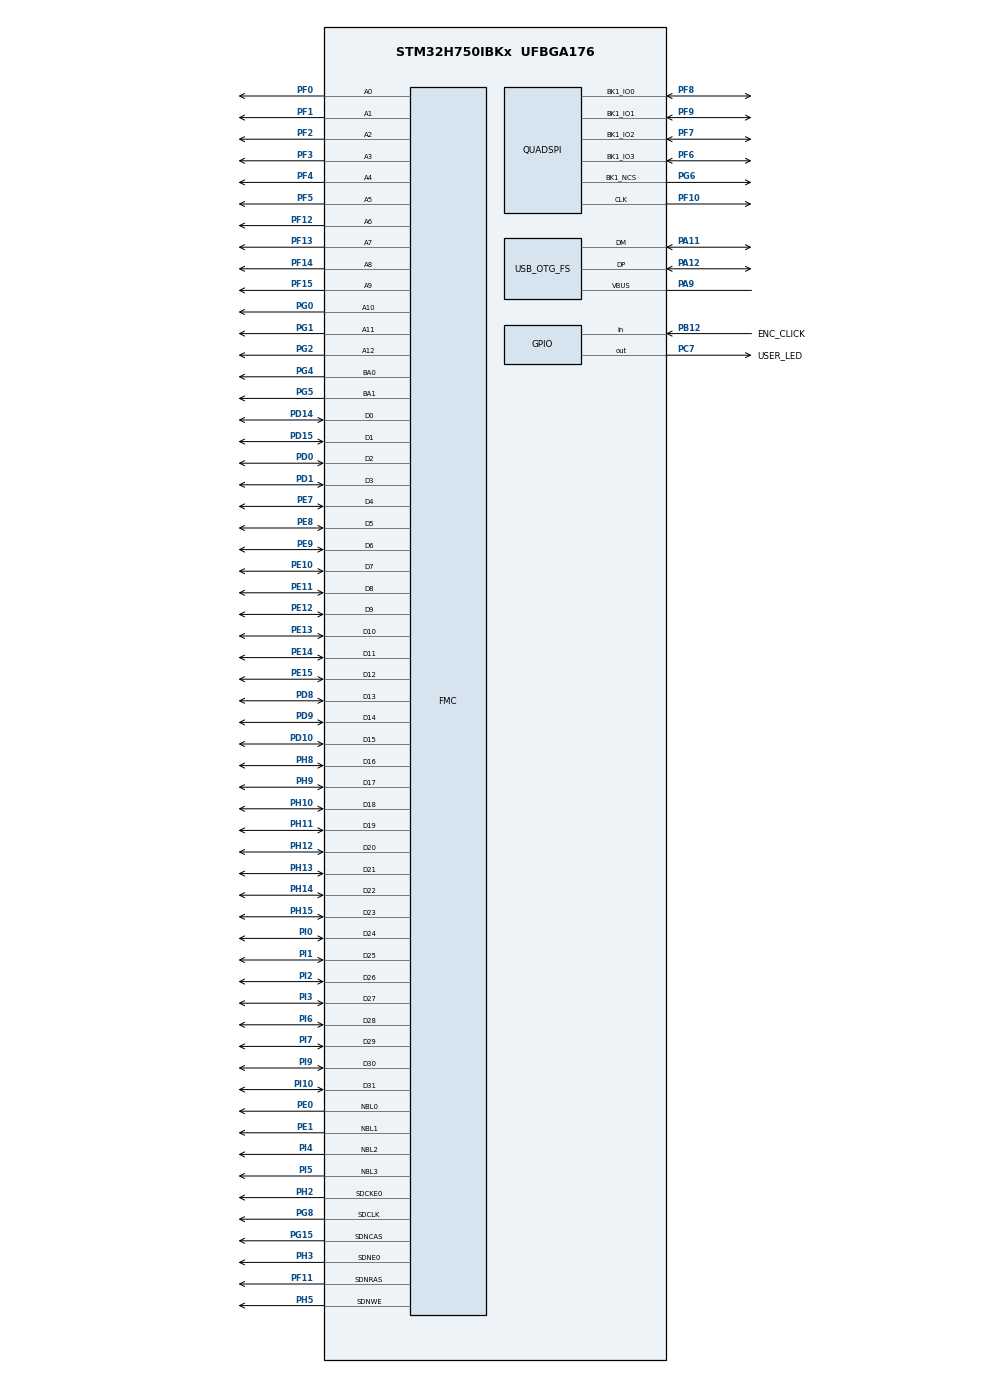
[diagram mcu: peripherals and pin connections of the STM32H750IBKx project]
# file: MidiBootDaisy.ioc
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CORTEX_M7.MPU_Control=__NULL
IWDG1.Prescaler=IWDG_PRESCALER_128
IWDG1.Reload=8*32000/128
IWDG1.Window=8*32000/128
Mcu.Family=STM32H7
Mcu.Name=STM32H750IBKx
Mcu.Package=UFBGA176
NVIC.OTG_FS_IRQn=true\:0\:0\:false\:false\:true\:false\:true
NVIC.PriorityGroup=NVIC_PRIORITYGROUP_4
NVIC.QUADSPI_IRQn=true\:0\:0\:false\:false\:true\:true\:true
PA11.GPIO_Speed=GPIO_SPEED_FREQ_VERY_HIGH
PA11.Mode=Device_Only
PA11.Signal=USB_OTG_FS_DM
PA12.GPIO_Speed=GPIO_SPEED_FREQ_VERY_HIGH
PA12.Mode=Device_Only
PA12.Signal=USB_OTG_FS_DP
PA13\ (JTMS/SWDIO).Mode=JTAG_4_pins
PA13\ (JTMS/SWDIO).Signal=DEBUG_JTMS-SWDIO
PA14\ (JTCK/SWCLK).Mode=JTAG_4_pins
PA14\ (JTCK/SWCLK).Signal=DEBUG_JTCK-SWCLK
PA15\ (JTDI).Mode=JTAG_4_pins
PA15\ (JTDI).Signal=DEBUG_JTDI
PA9.Mode=Activate_VBUS
PA9.Signal=USB_OTG_FS_VBUS
PB12.GPIO_Label=ENC_CLICK
PB12.GPIO_PuPd=GPIO_PULLUP
PB12.Signal=GPIO_Input
PB14.Signal=USB_OTG_HS_DM
PB15.Signal=USB_OTG_HS_DP
PB3\ (JTDO/TRACESWO).Mode=JTAG_4_pins
PB3\ (JTDO/TRACESWO).Signal=DEBUG_JTDO-SWO
PC7.GPIO_Label=USER_LED
PC7.Signal=GPIO_Output
PD0.Signal=FMC_D2_DA2
PD1.Signal=FMC_D3_DA3
PD10.Signal=FMC_D15_DA15
PD14.Signal=FMC_D0_DA0
PD15.Signal=FMC_D1_DA1
PD8.Signal=FMC_D13_DA13
PD9.Signal=FMC_D14_DA14
PE0.Signal=FMC_NBL0
PE1.Signal=FMC_NBL1
PE10.Signal=FMC_D7_DA7
PE11.Signal=FMC_D8_DA8
PE12.Signal=FMC_D9_DA9
PE13.Signal=FMC_D10_DA10
PE14.Signal=FMC_D11_DA11
PE15.Signal=FMC_D12_DA12
PE7.Signal=FMC_D4_DA4
PE8.Signal=FMC_D5_DA5
PE9.Signal=FMC_D6_DA6
PF0.Signal=FMC_A0
PF1.Signal=FMC_A1
PF10.GPIO_Speed=GPIO_SPEED_FREQ_VERY_HIGH
PF10.Mode=Single Bank 1
PF10.Signal=QUADSPI_CLK
PF11.Signal=FMC_SDNRAS
PF12.Signal=FMC_A6
PF13.Signal=FMC_A7
PF14.Signal=FMC_A8
PF15.Signal=FMC_A9
PF2.Signal=FMC_A2
PF3.Signal=FMC_A3
PF4.Signal=FMC_A4
PF5.Signal=FMC_A5
PF6.GPIO_Speed=GPIO_SPEED_FREQ_VERY_HIGH
PF6.Mode=Single Bank 1
PF6.Signal=QUADSPI_BK1_IO3
PF7.GPIO_Speed=GPIO_SPEED_FREQ_VERY_HIGH
PF7.Mode=Single Bank 1
PF7.Signal=QUADSPI_BK1_IO2
PF8.GPIO_Speed=GPIO_SPEED_FREQ_VERY_HIGH
PF8.Mode=Single Bank 1
PF8.Signal=QUADSPI_BK1_IO0
PF9.GPIO_Speed=GPIO_SPEED_FREQ_VERY_HIGH
PF9.Mode=Single Bank 1
PF9.Signal=QUADSPI_BK1_IO1
PG0.Signal=FMC_A10
PG1.Signal=FMC_A11
PG15.Signal=FMC_SDNCAS
PG2.Signal=FMC_A12
PG4.Signal=FMC_A14_BA0
PG5.Signal=FMC_A15_BA1
PG6.GPIO_Speed=GPIO_SPEED_FREQ_VERY_HIGH
PG6.Mode=Single Bank 1
PG6.Signal=QUADSPI_BK1_NCS
PG8.Signal=FMC_SDCLK
PH0-OSC_IN\ (PH0).Mode=HSE-External-Oscillator
PH0-OSC_IN\ (PH0).Signal=RCC_OSC_IN
PH1-OSC_OUT\ (PH1).Mode=HSE-External-Oscillator
PH1-OSC_OUT\ (PH1).Signal=RCC_OSC_OUT
PH10.Signal=FMC_D18
PH11.Signal=FMC_D19
PH12.Signal=FMC_D20
PH13.Signal=FMC_D21
PH14.Signal=FMC_D22
PH15.Signal=FMC_D23
PH2.Mode=SdramChipSelect1_1
PH2.Signal=FMC_SDCKE0
PH3.Mode=SdramChipSelect1_1
PH3.Signal=FMC_SDNE0
PH5.Signal=FMC_SDNWE
PH8.Signal=FMC_D16
PH9.Signal=FMC_D17
PI0.Signal=FMC_D24
PI1.Signal=FMC_D25
PI10.Signal=FMC_D31
PI2.Signal=FMC_D26
PI3.Signal=FMC_D27
PI4.Signal=FMC_NBL2
PI5.Signal=FMC_NBL3
PI6.Signal=FMC_D28
PI7.Signal=FMC_D29
PI9.Signal=FMC_D30
ProjectManager.HeapSize=0x2000
ProjectManager.StackSize=0x4000
ProjectManager.TargetToolchain=Makefile
QUADSPI.ChipSelectHighTime=QSPI_CS_HIGH_TIME_2_CYCLE
QUADSPI.ClockPrescaler=1
RCC.ADCCLockSelection=RCC_ADCCLKSOURCE_PLL3
RCC.ADCFreq_Value=49166666.666666664
RCC.APB1Freq_Value=100000000
RCC.APB2Freq_Value=100000000
RCC.APB3Freq_Value=100000000
RCC.APB4Freq_Value=100000000
RCC.CKPERSourceSelection=RCC_CLKPSOURCE_HSE
RCC.CortexFreq_Value=400000000
RCC.D1PPRE=RCC_APB3_DIV2
RCC.D2PPRE1=RCC_APB1_DIV2
RCC.D2PPRE2=RCC_APB2_DIV2
RCC.D3PPRE=RCC_APB4_DIV2
RCC.DIVM1=4
RCC.DIVM2=4
RCC.DIVM3=6
RCC.DIVN1=200
RCC.DIVN2=84
RCC.DIVN3=295
RCC.DIVP2=8
RCC.DIVP3=4
RCC.DIVQ1=5
RCC.DIVQ3=4
RCC.DIVR3=16
RCC.FMCCLockSelection=RCC_FMCCLKSOURCE_PLL2
RCC.HCLKFreq_Value=200000000
RCC.HPRE=RCC_HCLK_DIV2
RCC.HSE_VALUE=16000000
RCC.PLL2FRACN=0
RCC.PLL3FRACN=0
RCC.PLLFRACN=0
RCC.PLLSourceVirtual=RCC_PLLSOURCE_HSE
RCC.SAI1CLockSelection=RCC_SAI1CLKSOURCE_PLL3
RCC.SAI23CLockSelection=RCC_SAI23CLKSOURCE_PLL3
RCC.SDMMC1CLockSelection=RCC_SDMMCCLKSOURCE_PLL2
RCC.SYSCLKFreq_VALUE=400000000
RCC.SYSCLKSource=RCC_SYSCLKSOURCE_PLLCLK
RCC.USBCLockSelection=RCC_USBCLKSOURCE_HSI48
RCC.USBFreq_Value=48000000
SH.FMC_A0.0=FMC_A0,13b-sda1
SH.FMC_A1.0=FMC_A1,13b-sda1
SH.FMC_A10.0=FMC_A10,13b-sda1
SH.FMC_A11.0=FMC_A11,13b-sda1
SH.FMC_A12.0=FMC_A12,13b-sda1
SH.FMC_A14_BA0.0=FMC_BA0,FourSdramBanks1
SH.FMC_A15_BA1.0=FMC_BA1,FourSdramBanks1
SH.FMC_A2.0=FMC_A2,13b-sda1
SH.FMC_A3.0=FMC_A3,13b-sda1
SH.FMC_A4.0=FMC_A4,13b-sda1
SH.FMC_A5.0=FMC_A5,13b-sda1
SH.FMC_A6.0=FMC_A6,13b-sda1
SH.FMC_A7.0=FMC_A7,13b-sda1
SH.FMC_A8.0=FMC_A8,13b-sda1
SH.FMC_A9.0=FMC_A9,13b-sda1
SH.FMC_D0_DA0.0=FMC_D0,sd-32b-d1
SH.FMC_D10_DA10.0=FMC_D10,sd-32b-d1
SH.FMC_D11_DA11.0=FMC_D11,sd-32b-d1
SH.FMC_D12_DA12.0=FMC_D12,sd-32b-d1
SH.FMC_D13_DA13.0=FMC_D13,sd-32b-d1
SH.FMC_D14_DA14.0=FMC_D14,sd-32b-d1
SH.FMC_D15_DA15.0=FMC_D15,sd-32b-d1
SH.FMC_D16.0=FMC_D16,sd-32b-d1
SH.FMC_D17.0=FMC_D17,sd-32b-d1
SH.FMC_D18.0=FMC_D18,sd-32b-d1
SH.FMC_D19.0=FMC_D19,sd-32b-d1
SH.FMC_D1_DA1.0=FMC_D1,sd-32b-d1
SH.FMC_D20.0=FMC_D20,sd-32b-d1
SH.FMC_D21.0=FMC_D21,sd-32b-d1
SH.FMC_D22.0=FMC_D22,sd-32b-d1
SH.FMC_D23.0=FMC_D23,sd-32b-d1
SH.FMC_D24.0=FMC_D24,sd-32b-d1
SH.FMC_D25.0=FMC_D25,sd-32b-d1
SH.FMC_D26.0=FMC_D26,sd-32b-d1
SH.FMC_D27.0=FMC_D27,sd-32b-d1
SH.FMC_D28.0=FMC_D28,sd-32b-d1
SH.FMC_D29.0=FMC_D29,sd-32b-d1
SH.FMC_D2_DA2.0=FMC_D2,sd-32b-d1
SH.FMC_D30.0=FMC_D30,sd-32b-d1
SH.FMC_D31.0=FMC_D31,sd-32b-d1
SH.FMC_D3_DA3.0=FMC_D3,sd-32b-d1
SH.FMC_D4_DA4.0=FMC_D4,sd-32b-d1
SH.FMC_D5_DA5.0=FMC_D5,sd-32b-d1
SH.FMC_D6_DA6.0=FMC_D6,sd-32b-d1
SH.FMC_D7_DA7.0=FMC_D7,sd-32b-d1
SH.FMC_D8_DA8.0=FMC_D8,sd-32b-d1
SH.FMC_D9_DA9.0=FMC_D9,sd-32b-d1
SH.FMC_NBL0.0=FMC_NBL0,Sd4ByteEnable1
SH.FMC_NBL1.0=FMC_NBL1,Sd4ByteEnable1
SH.FMC_NBL2.0=FMC_NBL2,Sd4ByteEnable1
SH.FMC_NBL3.0=FMC_NBL3,Sd4ByteEnable1
SH.FMC_SDCLK.0=FMC_SDCLK,13b-sda1
SH.FMC_SDNCAS.0=FMC_SDNCAS,13b-sda1
SH.FMC_SDNRAS.0=FMC_SDNRAS,13b-sda1
SH.FMC_SDNWE.0=FMC_SDNWE,13b-sda1
USB_DEVICE.CLASS_NAME_FS=AUDIO
USB_DEVICE.MANUFACTURER_STRING-AUDIO_FS=Electrosmith
USB_DEVICE.PID_AUDIO_FS=0xDADA
USB_DEVICE.PRODUCT_STRING_AUDIO_FS=OWL-BOOT
USB_DEVICE.USBD_AUDIO_FREQ-AUDIO_FS=48000
USB_DEVICE.USBD_MAX_NUM_CONFIGURATION-AUDIO_FS=5
USB_DEVICE.USBD_MAX_NUM_INTERFACES-AUDIO_FS=5
USB_DEVICE.VID-AUDIO_FS=0x0155
USB_DEVICE.VirtualMode-AUDIO_FS=Audio
USB_DEVICE.VirtualModeFS=Audio_FS
USB_OTG_FS.VirtualMode=Device_Only
VP_IWDG1_VS_IWDG.Mode=IWDG_Activate
VP_USB_DEVICE_VS_USB_DEVICE_AUDIO_FS.Mode=AUDIO_FS
board=custom

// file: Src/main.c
/* USER CODE BEGIN Header */
/**
  ******************************************************************************
  * @file           : main.c
  * @brief          : Main program body
  ******************************************************************************
  * @attention
  *
  * <h2><center>&copy; Copyright (c) 2020 STMicroelectronics.
  * All rights reserved.</center></h2>
  *
  * This software component is licensed by ST under Ultimate Liberty license
  * SLA0044, the "License"; You may not use this file except in compliance with
  * the License. You may obtain a copy of the License at:
  *                             www.st.com/SLA0044
  *
  ******************************************************************************
  */
/* USER CODE END Header */
#include "main.h"
#include "usb_device.h"

/* USER CODE BEGIN Includes */
#include "device.h"
#include "errorhandlers.h"
#include "qspicontrol.h"
#include "FirmwareHeader.h"
#include "sdram.h"
#include "crc32.h"
/* USER CODE END Includes */

IWDG_HandleTypeDef hiwdg1;

QSPI_HandleTypeDef hqspi;

SDRAM_HandleTypeDef hsdram1;

/* USER CODE BEGIN PV */
/* Private variables ---------------------------------------------------------*/
/* USER CODE END PV */

void SystemClock_Config(void);
static void MX_GPIO_Init(void);
static void MX_FMC_Init(void);
static void MX_QUADSPI_Init(void);
static void MX_IWDG1_Init(void);
/* USER CODE BEGIN PFP */
/* Private function prototypes -----------------------------------------------*/

void setup(void);
void SDRAM_Initialization_Sequence(SDRAM_HandleTypeDef *hsdram);
void loop(void);
void setMessage(const char* msg);
struct FirmwareHeader* getFirmwareHeader(void);
int loadFirmware(void);

typedef  void (*pFunction)(void);

static int testMagic(){
  return *OWLBOOT_MAGIC_ADDRESS == OWLBOOT_MAGIC_NUMBER;
}

static int testLoop(){
  // Prevent reset cycles.
  // Check if we've been reset without zeroing the magic address,
  // which might indicate a corrupt firmware.
  return *OWLBOOT_MAGIC_ADDRESS == OWLBOOT_LOOP_NUMBER;
}

static int testButton(){
#ifdef USE_BOOT1_PIN
  return !(BOOT1_GPIO_Port->IDR & BOOT1_Pin);
#else
  return 0;
#endif
}

static int testNoProgram(){
  // NOTE: this must run only if QSPI flash is:
  // a. initialized successfully
  // b. is in memory-mapped mode
  return (*(__IO uint32_t*)APPLICATION_ADDRESS) != HEADER_MAGIC;
}

static int testWatchdogReset(){
  return __HAL_RCC_GET_FLAG(RCC_FLAG_IWDG1RST) != RESET;
}

static int testFirmwareHeader(){
  struct FirmwareHeader* header = getFirmwareHeader();
  uint32_t header_crc = crc32((void*)header, header->header_size - 4, 0);
  return header->checksum != header_crc;
}

/* USER CODE END PFP */

int main(void)
{

  /* MCU Configuration--------------------------------------------------------*/

  /* Reset of all peripherals, Initializes the Flash interface and the Systick. */
  HAL_Init();

  /* Configure the system clock */
  SystemClock_Config();

  /* Initialize all configured peripherals */
  MX_GPIO_Init();
  MX_FMC_Init();
  MX_QUADSPI_Init();
  MX_IWDG1_Init();
  MX_USB_DEVICE_Init();
  /* USER CODE BEGIN 2 */

  SDRAM_Initialization_Sequence(&hsdram1);
  MPU_Config();
  if (qspi_init(QSPI_MODE_MEMORY_MAPPED) != MEMORY_OK){
    // We can end here only if QSPI settings are misconfigured
    error(RUNTIME_ERROR, "Flash init error");
  }
  else {
    if(testMagic()){
      setMessage("Bootloader starting");
    }
    else if(testButton()){
      setMessage("Bootloader requested");
      }
    else if(testLoop()){
      error(RUNTIME_ERROR, "Unexpected firmware reset");
    }
    else if(testWatchdogReset()){
      error(RUNTIME_ERROR, "Watchdog reset");
    }
    else if(testNoProgram()){
      error(RUNTIME_ERROR, "No valid firmware");
    }
    else if(testFirmwareHeader()){
      error(RUNTIME_ERROR, "Invalid firmware header");
    }
    else if (loadFirmware()){
      // jump to application code

      /* Disable all interrupts */
      __disable_irq();

      RCC->CIER = 0x00000000;

      /* Disable and reset SysTick */
      SysTick->CTRL = 0;
      SysTick->LOAD = 0;
      SysTick->VAL = 0;

      /* Clear Interrupt Enable Register & Interrupt Pending Register */
      for (int i = 0;i < 8; i++) {
    	  NVIC->ICER[i]=0xFFFFFFFF;
	      NVIC->ICPR[i]=0xFFFFFFFF;
      }

      /* put marker in to prevent reset cycles */
      *OWLBOOT_MAGIC_ADDRESS = OWLBOOT_LOOP_NUMBER;

      /* Jump to user application */
      struct FirmwareHeader* header = getFirmwareHeader();

      // Enable IWDG if firmware has option bit set
      //if ((header->options >> OPT_IWDG_OFFSET) & OPT_IWDG_MASK)
        MX_IWDG1_Init();

      uint32_t JumpAddress = *(__IO uint32_t*) (header->isr_vector_address + 4);
      pFunction jumpToApplication = (pFunction) JumpAddress;
      /* Initialize user application's Stack Pointer */
      __set_MSP(*(__IO uint32_t*) header->isr_vector_address);

      jumpToApplication();
      for(;;);
    }
  }
  MX_IWDG1_Init();

  /* Clear reset flags */
  __HAL_RCC_CLEAR_RESET_FLAGS();

  /* Clear magic */
  *OWLBOOT_MAGIC_ADDRESS = 0;

  // Initialise
  setup();

  /* USER CODE END 2 */

  /* Infinite loop */
  /* USER CODE BEGIN WHILE */
  while (1)
  {
    loop();
#ifdef USE_IWDG
    IWDG1->KR = 0xaaaa; // reset the watchdog timer
#endif
    /* USER CODE END WHILE */

  }
}

void SystemClock_Config(void)
{
  RCC_OscInitTypeDef RCC_OscInitStruct = {0};
  RCC_ClkInitTypeDef RCC_ClkInitStruct = {0};
  RCC_PeriphCLKInitTypeDef PeriphClkInitStruct = {0};

  /** Supply configuration update enable
  */
  HAL_PWREx_ConfigSupply(PWR_LDO_SUPPLY);
  /** Configure the main internal regulator output voltage
  */
  __HAL_PWR_VOLTAGESCALING_CONFIG(PWR_REGULATOR_VOLTAGE_SCALE1);

  while(!__HAL_PWR_GET_FLAG(PWR_FLAG_VOSRDY)) {}
  /** Macro to configure the PLL clock source
  */
  __HAL_RCC_PLL_PLLSOURCE_CONFIG(RCC_PLLSOURCE_HSE);
  /** Initializes the RCC Oscillators according to the specified parameters
  * in the RCC_OscInitTypeDef structure.
  */
  RCC_OscInitStruct.OscillatorType = RCC_OSCILLATORTYPE_HSI48|RCC_OSCILLATORTYPE_LSI
                              |RCC_OSCILLATORTYPE_HSE;
  RCC_OscInitStruct.HSEState = RCC_HSE_ON;
  RCC_OscInitStruct.LSIState = RCC_LSI_ON;
  RCC_OscInitStruct.HSI48State = RCC_HSI48_ON;
  RCC_OscInitStruct.PLL.PLLState = RCC_PLL_ON;
  RCC_OscInitStruct.PLL.PLLSource = RCC_PLLSOURCE_HSE;
  RCC_OscInitStruct.PLL.PLLM = 4;
  RCC_OscInitStruct.PLL.PLLN = 200;
  RCC_OscInitStruct.PLL.PLLP = 2;
  RCC_OscInitStruct.PLL.PLLQ = 5;
  RCC_OscInitStruct.PLL.PLLR = 2;
  RCC_OscInitStruct.PLL.PLLRGE = RCC_PLL1VCIRANGE_2;
  RCC_OscInitStruct.PLL.PLLVCOSEL = RCC_PLL1VCOWIDE;
  RCC_OscInitStruct.PLL.PLLFRACN = 0;
  if (HAL_RCC_OscConfig(&RCC_OscInitStruct) != HAL_OK)
  {
    Error_Handler();
  }
  /** Initializes the CPU, AHB and APB buses clocks
  */
  RCC_ClkInitStruct.ClockType = RCC_CLOCKTYPE_HCLK|RCC_CLOCKTYPE_SYSCLK
                              |RCC_CLOCKTYPE_PCLK1|RCC_CLOCKTYPE_PCLK2
                              |RCC_CLOCKTYPE_D3PCLK1|RCC_CLOCKTYPE_D1PCLK1;
  RCC_ClkInitStruct.SYSCLKSource = RCC_SYSCLKSOURCE_PLLCLK;
  RCC_ClkInitStruct.SYSCLKDivider = RCC_SYSCLK_DIV1;
  RCC_ClkInitStruct.AHBCLKDivider = RCC_HCLK_DIV2;
  RCC_ClkInitStruct.APB3CLKDivider = RCC_APB3_DIV2;
  RCC_ClkInitStruct.APB1CLKDivider = RCC_APB1_DIV2;
  RCC_ClkInitStruct.APB2CLKDivider = RCC_APB2_DIV2;
  RCC_ClkInitStruct.APB4CLKDivider = RCC_APB4_DIV2;

  if (HAL_RCC_ClockConfig(&RCC_ClkInitStruct, FLASH_LATENCY_2) != HAL_OK)
  {
    Error_Handler();
  }
  PeriphClkInitStruct.PeriphClockSelection = RCC_PERIPHCLK_USB|RCC_PERIPHCLK_QSPI
                              |RCC_PERIPHCLK_FMC;
  PeriphClkInitStruct.PLL2.PLL2M = 4;
  PeriphClkInitStruct.PLL2.PLL2N = 84;
  PeriphClkInitStruct.PLL2.PLL2P = 8;
  PeriphClkInitStruct.PLL2.PLL2Q = 2;
  PeriphClkInitStruct.PLL2.PLL2R = 2;
  PeriphClkInitStruct.PLL2.PLL2RGE = RCC_PLL2VCIRANGE_2;
  PeriphClkInitStruct.PLL2.PLL2VCOSEL = RCC_PLL2VCOWIDE;
  PeriphClkInitStruct.PLL2.PLL2FRACN = 0;
  PeriphClkInitStruct.FmcClockSelection = RCC_FMCCLKSOURCE_PLL2;
  PeriphClkInitStruct.QspiClockSelection = RCC_QSPICLKSOURCE_D1HCLK;
  PeriphClkInitStruct.UsbClockSelection = RCC_USBCLKSOURCE_HSI48;
  if (HAL_RCCEx_PeriphCLKConfig(&PeriphClkInitStruct) != HAL_OK)
  {
    Error_Handler();
  }
  /** Enable USB Voltage detector
  */
  HAL_PWREx_EnableUSBVoltageDetector();
}

static void MX_IWDG1_Init(void)
{

  /* USER CODE BEGIN IWDG1_Init 1 */
#ifdef USE_IWDG
  /* USER CODE END IWDG1_Init 1 */
  hiwdg1.Instance = IWDG1;
  hiwdg1.Init.Prescaler = IWDG_PRESCALER_128;
  hiwdg1.Init.Window = 8*32000/128;
  hiwdg1.Init.Reload = 8*32000/128;
  if (HAL_IWDG_Init(&hiwdg1) != HAL_OK)
  {
    Error_Handler();
  }
  /* USER CODE BEGIN IWDG1_Init 2 */
#endif
  /* USER CODE END IWDG1_Init 2 */

}

static void MX_QUADSPI_Init(void)
{

  /* QUADSPI parameter configuration*/
  hqspi.Instance = QUADSPI;
  hqspi.Init.ClockPrescaler = 1;
  hqspi.Init.FifoThreshold = 1;
  hqspi.Init.SampleShifting = QSPI_SAMPLE_SHIFTING_NONE;
  hqspi.Init.FlashSize = 1;
  hqspi.Init.ChipSelectHighTime = QSPI_CS_HIGH_TIME_2_CYCLE;
  hqspi.Init.ClockMode = QSPI_CLOCK_MODE_0;
  hqspi.Init.FlashID = QSPI_FLASH_ID_1;
  hqspi.Init.DualFlash = QSPI_DUALFLASH_DISABLE;
  if (HAL_QSPI_Init(&hqspi) != HAL_OK)
  {
    Error_Handler();
  }

}

/* FMC initialization function */
static void MX_FMC_Init(void)
{

  FMC_SDRAM_TimingTypeDef SdramTiming = {0};

  /** Perform the SDRAM1 memory initialization sequence
  */
  hsdram1.Instance = FMC_SDRAM_DEVICE;
  /* hsdram1.Init */
  hsdram1.Init.SDBank = FMC_SDRAM_BANK1;
  hsdram1.Init.ColumnBitsNumber = FMC_SDRAM_COLUMN_BITS_NUM_8;
  hsdram1.Init.RowBitsNumber = FMC_SDRAM_ROW_BITS_NUM_13;
  hsdram1.Init.MemoryDataWidth = FMC_SDRAM_MEM_BUS_WIDTH_32;
  hsdram1.Init.InternalBankNumber = FMC_SDRAM_INTERN_BANKS_NUM_4;
  hsdram1.Init.CASLatency = FMC_SDRAM_CAS_LATENCY_1;
  hsdram1.Init.WriteProtection = FMC_SDRAM_WRITE_PROTECTION_DISABLE;
  hsdram1.Init.SDClockPeriod = FMC_SDRAM_CLOCK_DISABLE;
  hsdram1.Init.ReadBurst = FMC_SDRAM_RBURST_DISABLE;
  hsdram1.Init.ReadPipeDelay = FMC_SDRAM_RPIPE_DELAY_0;
  /* SdramTiming */
  SdramTiming.LoadToActiveDelay = 16;
  SdramTiming.ExitSelfRefreshDelay = 16;
  SdramTiming.SelfRefreshTime = 16;
  SdramTiming.RowCycleDelay = 16;
  SdramTiming.WriteRecoveryTime = 16;
  SdramTiming.RPDelay = 16;
  SdramTiming.RCDDelay = 16;

  if (HAL_SDRAM_Init(&hsdram1, &SdramTiming) != HAL_OK)
  {
    Error_Handler( );
  }

}

static void MX_GPIO_Init(void)
{
  GPIO_InitTypeDef GPIO_InitStruct = {0};

  /* GPIO Ports Clock Enable */
  __HAL_RCC_GPIOE_CLK_ENABLE();
  __HAL_RCC_GPIOB_CLK_ENABLE();
  __HAL_RCC_GPIOA_CLK_ENABLE();
  __HAL_RCC_GPIOG_CLK_ENABLE();
  __HAL_RCC_GPIOD_CLK_ENABLE();
  __HAL_RCC_GPIOI_CLK_ENABLE();
  __HAL_RCC_GPIOH_CLK_ENABLE();
  __HAL_RCC_GPIOF_CLK_ENABLE();
  __HAL_RCC_GPIOC_CLK_ENABLE();

#ifdef USER_LED_Pin
  /*Configure GPIO pin Output Level */
  HAL_GPIO_WritePin(USER_LED_GPIO_Port, USER_LED_Pin, USER_LED_INVERTED ? GPIO_PIN_SET : GPIO_PIN_RESET);

  /*Configure GPIO pin : USER_LED_Pin */
  GPIO_InitStruct.Pin = USER_LED_Pin;
  GPIO_InitStruct.Mode = GPIO_MODE_OUTPUT_PP;
  GPIO_InitStruct.Pull = GPIO_NOPULL;
  GPIO_InitStruct.Speed = GPIO_SPEED_FREQ_LOW;
  HAL_GPIO_Init(USER_LED_GPIO_Port, &GPIO_InitStruct);
#endif

#ifdef ERROR_LED_Pin
  /*Configure GPIO pin Output Level */
  HAL_GPIO_WritePin(ERROR_LED_GPIO_Port, ERROR_LED_Pin, ERROR_LED_INVERTED ? GPIO_PIN_SET : GPIO_PIN_RESET);

  /*Configure GPIO pin : ERROR_LED_Pin */
  GPIO_InitStruct.Pin = ERROR_LED_Pin;
  GPIO_InitStruct.Mode = GPIO_MODE_OUTPUT_PP;
  GPIO_InitStruct.Pull = GPIO_NOPULL;
  GPIO_InitStruct.Speed = GPIO_SPEED_FREQ_LOW;
  HAL_GPIO_Init(ERROR_LED_GPIO_Port, &GPIO_InitStruct);
#endif

#ifdef ENC_CLICK_Pin
  /*Configure GPIO pin : ENC_CLICK_Pin */
  GPIO_InitStruct.Pin = ENC_CLICK_Pin;
  GPIO_InitStruct.Mode = GPIO_MODE_INPUT;
  GPIO_InitStruct.Pull = GPIO_PULLUP;
  HAL_GPIO_Init(ENC_CLICK_GPIO_Port, &GPIO_InitStruct);
#endif

#if !defined(PATCH_SM)
  /*Configure GPIO pins : PB14 PB15 */
  GPIO_InitStruct.Pin = GPIO_PIN_14|GPIO_PIN_15;
  GPIO_InitStruct.Mode = GPIO_MODE_AF_PP;
  GPIO_InitStruct.Pull = GPIO_NOPULL;
  GPIO_InitStruct.Speed = GPIO_SPEED_FREQ_LOW;
  GPIO_InitStruct.Alternate = GPIO_AF12_OTG2_FS;
  HAL_GPIO_Init(GPIOB, &GPIO_InitStruct);
#endif

#ifdef USE_BOOT1_PIN
  /*Configure GPIO pin : BOOT1_Pin */
  GPIO_InitStruct.Pin = BOOT1_Pin;
  GPIO_InitStruct.Mode = GPIO_MODE_INPUT;
  GPIO_InitStruct.Pull = GPIO_PULLUP;
  HAL_GPIO_Init(BOOT1_GPIO_Port, &GPIO_InitStruct);
#endif

}

void Error_Handler(void)
{
  /* USER CODE BEGIN Error_Handler_Debug */
#ifdef DEBUG
  __asm__("BKPT");
#else
  NVIC_SystemReset();
#endif
  /* USER CODE END Error_Handler_Debug */
}

#ifdef  USE_FULL_ASSERT
/**
  * @brief  Reports the name of the source file and the source line number
  *         where the assert_param error has occurred.
  * @param  file: pointer to the source file name
  * @param  line: assert_param error line source number
  * @retval None
  */
void assert_failed(uint8_t *file, uint32_t line)
{
  /* USER CODE BEGIN 6 */
#ifdef DEBUG
  __asm__("BKPT");
#else
  NVIC_SystemReset();
#endif
  /* USER CODE END 6 */
}
#endif /* USE_FULL_ASSERT */

/************************ (C) COPYRIGHT STMicroelectronics *****END OF FILE****/
